# A hand-written LEF 5.8 technology and cell library in the style of an
# open PDK: two routing layers with a cut layer between them, a fixed and
# a generated via, a core site, and two macros (an inverter and a NAND2)
# with pin geometry and obstructions.
VERSION 5.8 ;
BUSBITCHARS "[]" ;
DIVIDERCHAR "/" ;
UNITS
  DATABASE MICRONS 1000 ;
END UNITS
MANUFACTURINGGRID 0.005 ;
CLEARANCEMEASURE EUCLIDEAN ;
USEMINSPACING OBS OFF ;
PROPERTYDEFINITIONS
  MACRO cellClass STRING ;
  LAYER minArea REAL RANGE 0 10 ;
END PROPERTYDEFINITIONS
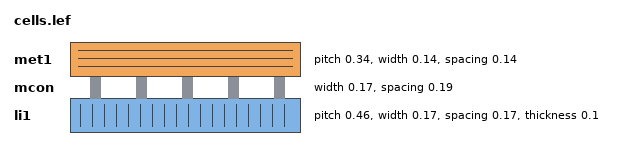
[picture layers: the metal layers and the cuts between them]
LAYER li1
  TYPE ROUTING ;
  DIRECTION VERTICAL ;
  PITCH 0.46 ;
  OFFSET 0.23 ;
  WIDTH 0.17 ;
  SPACING 0.17 ;
  AREA 0.0561 ;
  THICKNESS 0.1 ;
  RESISTANCE RPERSQ 12.2 ;
  CAPACITANCE CPERSQDIST 3.6e-05 ;
  EDGECAPACITANCE 4.1e-05 ;
  PROPERTY minArea 0.0561 ;
END li1
LAYER mcon
  TYPE CUT ;
  WIDTH 0.17 ;
  SPACING 0.19 ;
  RESISTANCE 9.3 ;
END mcon
LAYER met1
  TYPE ROUTING ;
  DIRECTION HORIZONTAL ;
  PITCH 0.34 ;
  OFFSET 0.17 ;
  WIDTH 0.14 ;
  MINWIDTH 0.14 ;
  SPACING 0.14 ;
  SPACING 0.28 RANGE 3 100 ;
  AREA 0.083 ;
  RESISTANCE RPERSQ 0.125 ;
  CAPACITANCE CPERSQDIST 2.5e-05 ;
  SPACINGTABLE PARALLELRUNLENGTH 0 3 WIDTH 0 0.14 0.14 WIDTH 3 0.28 0.28 ;
  ANTENNADIFFSIDEAREARATIO PWL ( ( 0 75 ) ( 0.0125 75 ) ) ;
END met1
VIA mcon_fixed DEFAULT
  LAYER li1 ;
    RECT -0.085 -0.085 0.085 0.085 ;
  LAYER mcon ;
    RECT -0.085 -0.085 0.085 0.085 ;
  LAYER met1 ;
    RECT -0.085 -0.095 0.085 0.095 ;
END mcon_fixed
VIA mcon_gen GENERATED
  VIARULE mcon_rule ;
  CUTSIZE 0.17 0.17 ;
  LAYERS li1 mcon met1 ;
  CUTSPACING 0.19 0.19 ;
  ENCLOSURE 0 0 0 0.01 ;
  ROWCOL 1 1 ;
  RESISTANCE 9.3 ;
END mcon_gen
VIARULE mcon_rule GENERATE DEFAULT
  LAYER li1 ;
    ENCLOSURE 0 0 ;
  LAYER met1 ;
    ENCLOSURE 0 0.01 ;
  LAYER mcon ;
    RECT -0.085 -0.085 0.085 0.085 ;
    SPACING 0.36 BY 0.36 ;
END mcon_rule
SITE demohd
  CLASS CORE ;
  SYMMETRY Y ;
  SIZE 0.46 BY 2.72 ;
END demohd
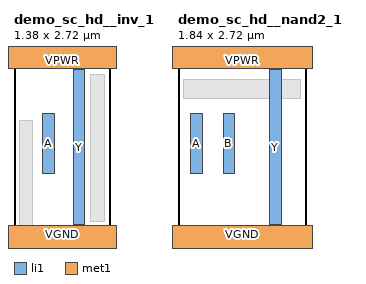
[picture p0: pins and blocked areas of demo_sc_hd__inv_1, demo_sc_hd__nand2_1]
MACRO demo_sc_hd__inv_1
  CLASS CORE ;
  FOREIGN demo_sc_hd__inv_1 0 0 ;
  ORIGIN 0 0 ;
  SIZE 1.38 BY 2.72 ;
  SYMMETRY X Y R90 ;
  SITE demohd ;
  PIN A
    DIRECTION INPUT ;
    USE SIGNAL ;
    ANTENNAGATEAREA 0.1575 ;
    PORT
      LAYER li1 ;
        RECT 0.415 0.985 0.585 1.835 ;
    END
  END A
  PIN Y
    DIRECTION OUTPUT ;
    USE SIGNAL ;
    ANTENNADIFFAREA 0.132 ;
    PORT
      LAYER li1 ;
        RECT 0.845 0.255 1.015 2.465 ;
    END
  END Y
  PIN VPWR
    DIRECTION INOUT ;
    USE POWER ;
    SHAPE ABUTMENT ;
    PORT
      LAYER met1 ;
        RECT -0.19 2.48 1.57 2.96 ;
      VIA 0.69 2.72 mcon_fixed ;
    END
  END VPWR
  PIN VGND
    DIRECTION INOUT ;
    USE GROUND ;
    SHAPE ABUTMENT ;
    PORT
      LAYER met1 ;
        RECT -0.19 -0.24 1.57 0.24 ;
    END
  END VGND
  OBS
    LAYER li1 ;
      RECT 0.085 0.085 0.265 1.735 ;
      POLYGON 1.1 0.3 1.3 0.3 1.3 2.4 1.1 2.4 ;
  END
  PROPERTY cellClass "inverter" ;
END demo_sc_hd__inv_1
MACRO demo_sc_hd__nand2_1
  CLASS CORE ;
  FOREIGN demo_sc_hd__nand2_1 0 0 ;
  ORIGIN 0 0 ;
  SIZE 1.84 BY 2.72 ;
  SYMMETRY X Y R90 ;
  SITE demohd ;
  PIN A
    DIRECTION INPUT ;
    USE SIGNAL ;
    PORT
      LAYER li1 ;
        RECT 0.185 0.985 0.355 1.835 ;
    END
  END A
  PIN B
    DIRECTION INPUT ;
    USE SIGNAL ;
    PORT
      LAYER li1 ;
        RECT 0.645 0.985 0.815 1.835 ;
    END
  END B
  PIN Y
    DIRECTION OUTPUT ;
    USE SIGNAL ;
    PORT
      LAYER li1 ;
        RECT 1.305 0.255 1.475 2.465 ;
    END
  END Y
  PIN VPWR
    DIRECTION INOUT ;
    USE POWER ;
    SHAPE ABUTMENT ;
    PORT
      LAYER met1 ;
        RECT -0.19 2.48 2.03 2.96 ;
    END
  END VPWR
  PIN VGND
    DIRECTION INOUT ;
    USE GROUND ;
    SHAPE ABUTMENT ;
    PORT
      LAYER met1 ;
        RECT -0.19 -0.24 2.03 0.24 ;
    END
  END VGND
  OBS
    LAYER li1 ;
      RECT 0.085 2.055 1.755 2.325 ;
  END
  PROPERTY cellClass "nand" ;
END demo_sc_hd__nand2_1
END LIBRARY
